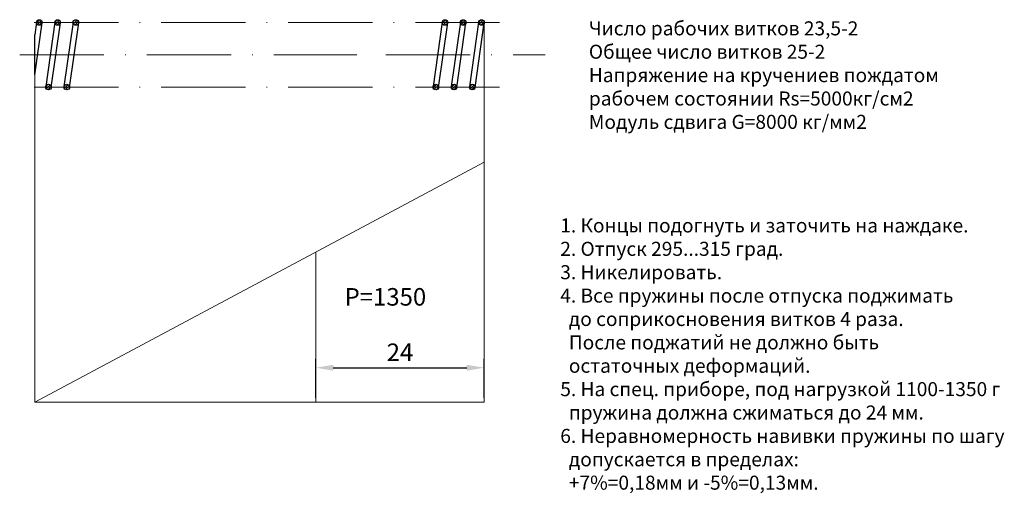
# Model space of a CAD drawing. Units: millimetres. Extents: x -62 to 78, y -63 to 5.
import ezdxf

# ---------------------------------------------------------------- set-up
doc = ezdxf.new("R2010")
doc.units = ezdxf.units.MM
doc.linetypes.add('ACAD_ISO10W100', pattern=[18, 12, -3, 0, -3])
doc.dimstyles.new('ISO-25', dxfattribs={"dimtxt": 2.5, "dimasz": 2.5, "dimexe": 1.25, "dimexo": 0.625, "dimtad": 1, "dimtxsty": 'Standard', "dimcen": 2.5, "dimadec": 0, "dimazin": 0, "dimtfac": 1, "dimtmove": 0, "dimatfit": 3, "dimfxl": 0, "dimarcsym": 0})

# ---------------------------------------------------------------- blocks, each defined once
blk = doc.blocks.new('*D4')
at = {"color": 0, "lineweight": -2}
for p, q in [((-20, -48.88), (-20, -43.36)), ((4, -48.88), (4, -43.36)), ((-17.5, -44.61), (1.5, -44.61))]:
    blk.add_line(p, q, dxfattribs=at)
at = {"color": 0, "lineweight": 15}
for points in [[(-17.5, -44.19), (-17.5, -45.03), (-20, -44.61)], [(1.5, -44.19), (1.5, -45.03), (4, -44.61)]]:
    blk.add_solid(points, dxfattribs=at)
at = {"layer": 'Defpoints', "color": 0, "lineweight": 15}
for p in [(4, -44.61), (-20, -49.5), (4, -49.5)]:
    blk.add_point(p, dxfattribs=at)
at = {"color": 0, "lineweight": 15, "insert": (-8, -42.73), "char_height": 2.5, "attachment_point": 5}
blk.add_mtext('24', dxfattribs=at)

msp = doc.modelspace()

# ---------------------------------------------------------------- hatches: boundary and pattern name
at = {"lineweight": 15}
h = msp.add_hatch(dxfattribs=at)
h.set_pattern_fill('ANSI31', scale=0.08, style=0)
h.paths.add_polyline_path([(-59.75, 4.6), (-58.95, 4.6, 1)])
h.paths.add_polyline_path([(-58.95, 4.6), (-59.75, 4.6, 1)])
h.paths.add_polyline_path([(-57.15, 4.6), (-56.35, 4.6, 1)])
h.paths.add_polyline_path([(-56.35, 4.6), (-57.15, 4.6, 1)])
h.paths.add_polyline_path([(-54.55, 4.6), (-53.75, 4.6, 1)])
h.paths.add_polyline_path([(-53.75, 4.6), (-54.55, 4.6, 1)])
h = msp.add_hatch(dxfattribs=at)
h.set_pattern_fill('ANSI31', scale=0.08, style=0)
h.paths.add_polyline_path([(-2, 4.6), (-1.2, 4.6, 1)])
h.paths.add_polyline_path([(-1.2, 4.6), (-2, 4.6, 1)])
h.paths.add_polyline_path([(0.6, 4.6), (1.4, 4.6, 1)])
h.paths.add_polyline_path([(1.4, 4.6), (0.6, 4.6, 1)])
h.paths.add_polyline_path([(3.2, 4.6), (4, 4.6, 1)])
h.paths.add_polyline_path([(4, 4.6), (3.2, 4.6, 1)])
h = msp.add_hatch(dxfattribs=at)
h.set_pattern_fill('ANSI31', scale=0.08, style=0)
h.paths.add_polyline_path([(-58.45, -4.6), (-57.65, -4.6, 1)])
h.paths.add_polyline_path([(-57.65, -4.6), (-58.45, -4.6, 1)])
h.paths.add_polyline_path([(-55.85, -4.6), (-55.05, -4.6, 1)])
h.paths.add_polyline_path([(-55.05, -4.6), (-55.85, -4.6, 1)])
h = msp.add_hatch(dxfattribs=at)
h.set_pattern_fill('ANSI31', scale=0.08, style=0)
h.paths.add_polyline_path([(-3.3, -4.6), (-2.5, -4.6, 1)])
h.paths.add_polyline_path([(-2.5, -4.6), (-3.3, -4.6, 1)])
h.paths.add_polyline_path([(-0.7, -4.6), (0.1, -4.6, 1)])
h.paths.add_polyline_path([(0.1, -4.6), (-0.7, -4.6, 1)])
h.paths.add_polyline_path([(1.9, -4.6), (2.7, -4.6, 1)])
h.paths.add_polyline_path([(2.7, -4.6), (1.9, -4.6, 1)])

# ---------------------------------------------------------------- linework, layer by layer
at = {"color": 1, "linetype": 'ACAD_ISO10W100', "lineweight": 15}
for p, q in [((6.194, 4.6), (-62.155, 4.6)), ((-62.155, 0), (-14.155, 0)), ((-10, 0), (12.668, 0)), ((6.194, -4.6), (-62.155, -4.6))]:
    msp.add_line(p, q, dxfattribs=at)
at = {"color": 7, "lineweight": 30}
for p, q in [((-59.746, 4.656), (-60, 2.859)), ((-60, -2.859), (-58.954, 4.544)), ((-57.146, 4.656), (-58.446, -4.544)), ((-57.654, -4.656), (-56.354, 4.544)), ((-54.546, 4.656), (-55.846, -4.544)), ((-55.054, -4.656), (-53.754, 4.544)), ((-1.996, 4.656), (-3.296, -4.544)), ((-2.504, -4.656), (-1.204, 4.544)), ((0.604, 4.656), (-0.696, -4.544)), ((0.096, -4.656), (1.396, 4.544)), ((3.204, 4.656), (1.904, -4.544)), ((2.696, -4.656), (3.996, 4.544)), ((-60, -2.859), (-60, 2.859))]:
    msp.add_line(p, q, dxfattribs=at)
at = {"color": 7, "lineweight": 15}
for p, q in [((4, -49.505), (4, 4.6)), ((-60, -49.505), (-60, -2.859)), ((-60, -49.505), (4, -15.321)), ((-20, -49.505), (-20, -28.14)), ((4, -49.505), (-60, -49.505))]:
    msp.add_line(p, q, dxfattribs=at)
at = {"color": 7, "lineweight": 30}
for centre in [(-59.35, 4.6), (-56.75, 4.6), (-54.15, 4.6), (-1.6, 4.6), (1, 4.6), (3.6, 4.6), (-58.05, -4.6), (-55.45, -4.6), (-2.9, -4.6), (-0.3, -4.6), (2.3, -4.6)]:
    msp.add_circle(centre, 0.4, dxfattribs=at)

# ---------------------------------------------------------------- texts
for s, height, p in [('Число рабочих витков 23,5-2', 2, (18.896, 2.763)), ('Общее число витков 25-2', 2, (18.896, -0.57)), ('Напряжение на кручениев пождатом', 2, (18.896, -3.903)), ('рабочем состоянии Rs=5000кг/см2', 2, (18.896, -7.237)), ('Модуль сдвига G=8000 кг/мм2', 2, (18.896, -10.57)), ('1. Концы подогнуть и заточить на наждаке.', 2, (14.824, -25.33)), ('2. Отпуск 295...315 град.', 2, (14.824, -28.664)), ('3. Никелировать.', 2, (14.824, -31.997)), ('P=1350', 2.5, (-15.889, -35.759)), ('4. Все пружины после отпуска поджимать', 2, (14.824, -35.33)), ('  до соприкосновения витков 4 раза.', 2, (14.824, -38.664)), ('  После поджатий не должно быть', 2, (14.824, -41.997)), ('  остаточных деформаций.', 2, (14.824, -45.33)), ('5. На спец. приборе, под нагрузкой 1100-1350 г', 2, (14.824, -48.664)), ('  пружина должна сжиматься до 24 мм.', 2, (14.824, -51.997)), ('6. Неравномерность навивки пружины по шагу', 2, (14.824, -55.33)), ('  допускается в пределах:', 2, (14.824, -58.664)), ('  +7%=0,18мм и -5%=0,13мм.', 2, (14.824, -61.997))]:
    msp.add_text(s, height=height, dxfattribs=at).set_placement(p)

# ---------------------------------------------------------------- dimensions: what is measured, and where the dimension line sits
at = {"color": 7, "lineweight": 15}
dim = msp.add_linear_dim(base=(4, -44.609), p1=(-20, -49.505), p2=(4, -49.505), dimstyle='ISO-25', dxfattribs=at)
dim.commit()
dim.dimension.update_dxf_attribs({"geometry": '*D4', "text_midpoint": (-8, -42.734)})

doc.saveas('drawing.dxf')
